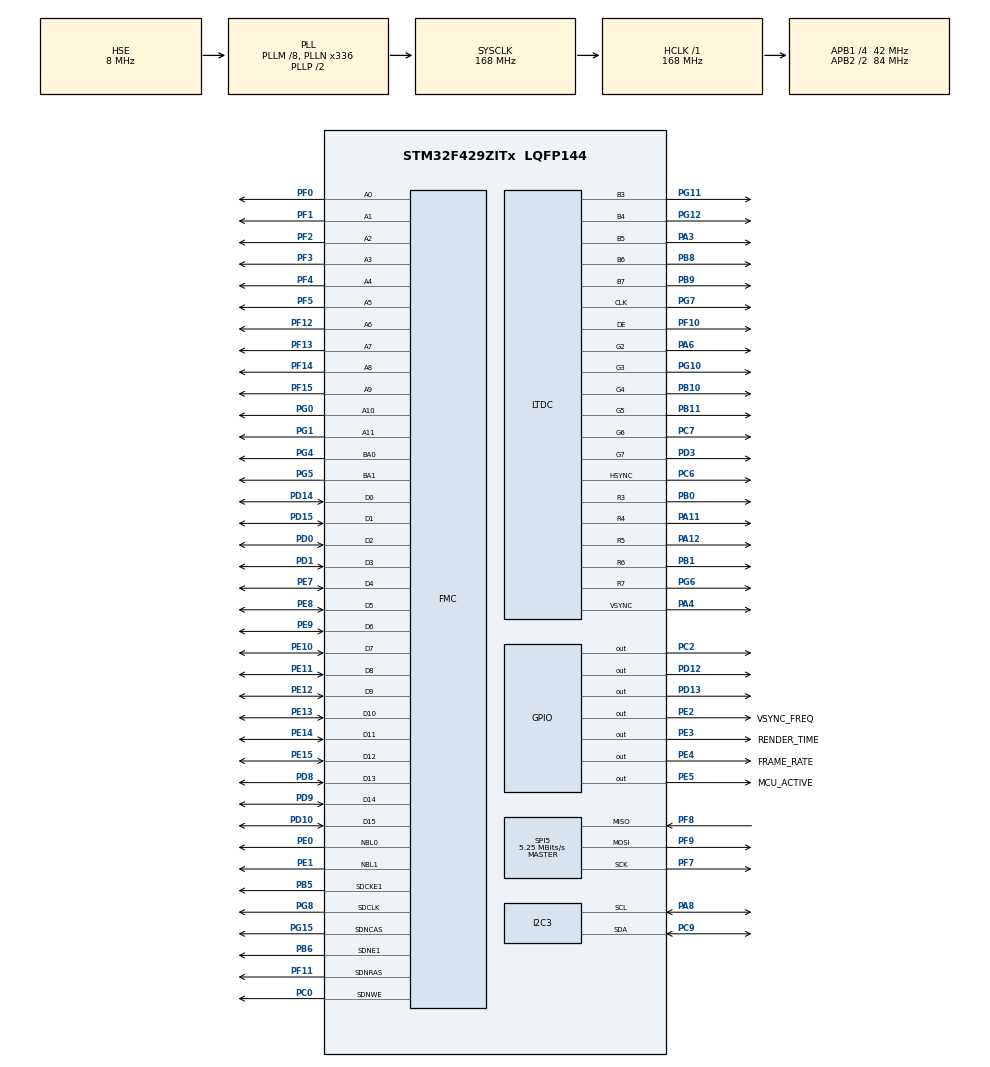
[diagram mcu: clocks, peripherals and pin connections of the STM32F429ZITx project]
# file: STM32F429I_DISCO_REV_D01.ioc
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DMA2D.ColorMode=DMA2D_OUTPUT_RGB565
FMC.CASLatency1=FMC_SDRAM_CAS_LATENCY_3
FMC.ExitSelfRefreshDelay1=7
FMC.LoadToActiveDelay1=2
FMC.RCDDelay1=2
FMC.RPDelay1=2
FMC.ReadPipeDelay1=FMC_SDRAM_RPIPE_DELAY_1
FMC.RowCycleDelay1=7
FMC.SDClockPeriod1=FMC_SDRAM_CLOCK_PERIOD_2
FMC.SelfRefreshTime1=4
FMC.WriteRecoveryTime1=3
FREERTOS.Tasks01=defaultTask,24,128,StartDefaultTask,Default,NULL,Dynamic,NULL,NULL;GUI_Task,24,8192,TouchGFX_Task,As external,NULL,Dynamic,NULL,NULL
FREERTOS.configMAX_PRIORITIES=56
FREERTOS.configTOTAL_HEAP_SIZE=65536
FREERTOS.configUSE_APPLICATION_TASK_TAG=1
I2C3.Analog_Filter=I2C_ANALOGFILTER_DISABLE
LTDC.ActiveH=320
LTDC.ActiveW=240
LTDC.Alpha_L0=255
LTDC.BlendingFactor1_L0=LTDC_BLENDING_FACTOR1_CA
LTDC.BlendingFactor2_L0=LTDC_BLENDING_FACTOR2_CA
LTDC.Blue_L0=0
LTDC.HBP=20
LTDC.HFP=10
LTDC.HSync=10
LTDC.ImageHeight_L0=320
LTDC.ImageWidth_L0=240
LTDC.Layers=0
LTDC.PixelFormat_L0=LTDC_PIXEL_FORMAT_RGB565
LTDC.VFP=4
LTDC.VSync=2
LTDC.WindowX1_L0=240
LTDC.WindowY1_L0=320
Mcu.Family=STM32F4
Mcu.Name=STM32F429ZITx
Mcu.Package=LQFP144
NVIC.DMA2D_IRQn=true\:5\:0\:true\:false\:true\:false\:true\:true\:true
NVIC.LTDC_IRQn=true\:5\:0\:true\:false\:true\:false\:true\:true\:true
NVIC.PriorityGroup=NVIC_PRIORITYGROUP_4
NVIC.TIM6_DAC_IRQn=true\:0\:0\:false\:false\:true\:false\:false\:true\:true
NVIC.TimeBase=TIM6_DAC_IRQn
NVIC.TimeBaseIP=TIM6
PA11.GPIO_Speed=GPIO_SPEED_FREQ_HIGH
PA11.Mode=RGB565
PA11.Signal=LTDC_R4
PA12.GPIO_Speed=GPIO_SPEED_FREQ_HIGH
PA12.Mode=RGB565
PA12.Signal=LTDC_R5
PA3.GPIO_Speed=GPIO_SPEED_FREQ_HIGH
PA3.Mode=RGB565
PA3.Signal=LTDC_B5
PA4.GPIO_Speed=GPIO_SPEED_FREQ_HIGH
PA4.Mode=RGB565
PA4.Signal=LTDC_VSYNC
PA6.GPIO_Speed=GPIO_SPEED_FREQ_HIGH
PA6.Mode=RGB565
PA6.Signal=LTDC_G2
PA8.GPIO_Pu=GPIO_PULLUP
PA8.Mode=I2C
PA8.Signal=I2C3_SCL
PB0.GPIO_Speed=GPIO_SPEED_FREQ_HIGH
PB0.Mode=RGB565
PB0.Signal=LTDC_R3
PB1.GPIO_Speed=GPIO_SPEED_FREQ_HIGH
PB1.Mode=RGB565
PB1.Signal=LTDC_R6
PB10.GPIO_Speed=GPIO_SPEED_FREQ_HIGH
PB10.Mode=RGB565
PB10.Signal=LTDC_G4
PB11.GPIO_Speed=GPIO_SPEED_FREQ_HIGH
PB11.Mode=RGB565
PB11.Signal=LTDC_G5
PB5.Mode=SdramChipSelect2_1
PB5.Signal=FMC_SDCKE1
PB6.Mode=SdramChipSelect2_1
PB6.Signal=FMC_SDNE1
PB8.GPIO_Speed=GPIO_SPEED_FREQ_HIGH
PB8.Mode=RGB565
PB8.Signal=LTDC_B6
PB9.GPIO_Speed=GPIO_SPEED_FREQ_HIGH
PB9.Mode=RGB565
PB9.Signal=LTDC_B7
PC0.Signal=FMC_SDNWE
PC2.GPIO_Speed=GPIO_SPEED_FREQ_HIGH
PC2.Signal=GPIO_Output
PC6.GPIO_Speed=GPIO_SPEED_FREQ_HIGH
PC6.Mode=RGB565
PC6.Signal=LTDC_HSYNC
PC7.GPIO_Speed=GPIO_SPEED_FREQ_HIGH
PC7.Mode=RGB565
PC7.Signal=LTDC_G6
PC9.GPIO_Pu=GPIO_PULLUP
PC9.Mode=I2C
PC9.Signal=I2C3_SDA
PD0.Signal=FMC_D2_DA2
PD1.Signal=FMC_D3_DA3
PD10.Signal=FMC_D15_DA15
PD12.GPIO_Speed=GPIO_SPEED_FREQ_HIGH
PD12.Signal=GPIO_Output
PD13.GPIO_Speed=GPIO_SPEED_FREQ_HIGH
PD13.Signal=GPIO_Output
PD14.Signal=FMC_D0_DA0
PD15.Signal=FMC_D1_DA1
PD3.GPIO_Speed=GPIO_SPEED_FREQ_HIGH
PD3.Mode=RGB565
PD3.Signal=LTDC_G7
PD8.Signal=FMC_D13_DA13
PD9.Signal=FMC_D14_DA14
PE0.Signal=FMC_NBL0
PE1.Signal=FMC_NBL1
PE10.Signal=FMC_D7_DA7
PE11.Signal=FMC_D8_DA8
PE12.Signal=FMC_D9_DA9
PE13.Signal=FMC_D10_DA10
PE14.Signal=FMC_D11_DA11
PE15.Signal=FMC_D12_DA12
PE2.GPIO_Label=VSYNC_FREQ
PE2.GPIO_Speed=GPIO_SPEED_FREQ_VERY_HIGH
PE2.Signal=GPIO_Output
PE3.GPIO_Label=RENDER_TIME
PE3.GPIO_Speed=GPIO_SPEED_FREQ_VERY_HIGH
PE3.Signal=GPIO_Output
PE4.GPIO_Label=FRAME_RATE
PE4.GPIO_Speed=GPIO_SPEED_FREQ_VERY_HIGH
PE4.Signal=GPIO_Output
PE5.GPIO_Label=MCU_ACTIVE
PE5.GPIO_Speed=GPIO_SPEED_FREQ_VERY_HIGH
PE5.Signal=GPIO_Output
PE7.Signal=FMC_D4_DA4
PE8.Signal=FMC_D5_DA5
PE9.Signal=FMC_D6_DA6
PF0.Signal=FMC_A0
PF1.Signal=FMC_A1
PF10.GPIO_Speed=GPIO_SPEED_FREQ_HIGH
PF10.Mode=RGB565
PF10.Signal=LTDC_DE
PF11.Signal=FMC_SDNRAS
PF12.Signal=FMC_A6
PF13.Signal=FMC_A7
PF14.Signal=FMC_A8
PF15.Signal=FMC_A9
PF2.Signal=FMC_A2
PF3.Signal=FMC_A3
PF4.Signal=FMC_A4
PF5.Signal=FMC_A5
PF7.Mode=Full_Duplex_Master
PF7.Signal=SPI5_SCK
PF8.Mode=Full_Duplex_Master
PF8.Signal=SPI5_MISO
PF9.Mode=Full_Duplex_Master
PF9.Signal=SPI5_MOSI
PG0.Signal=FMC_A10
PG1.Signal=FMC_A11
PG10.GPIO_Speed=GPIO_SPEED_FREQ_HIGH
PG10.Mode=RGB565
PG10.Signal=LTDC_G3
PG11.GPIO_Speed=GPIO_SPEED_FREQ_HIGH
PG11.Mode=RGB565
PG11.Signal=LTDC_B3
PG12.GPIO_Speed=GPIO_SPEED_FREQ_HIGH
PG12.Mode=RGB565
PG12.Signal=LTDC_B4
PG15.Signal=FMC_SDNCAS
PG4.Signal=FMC_A14_BA0
PG5.Signal=FMC_A15_BA1
PG6.GPIO_Speed=GPIO_SPEED_FREQ_HIGH
PG6.Mode=RGB565
PG6.Signal=LTDC_R7
PG7.GPIO_Speed=GPIO_SPEED_FREQ_HIGH
PG7.Mode=RGB565
PG7.Signal=LTDC_CLK
PG8.Signal=FMC_SDCLK
PH0/OSC_IN.Mode=HSE-External-Oscillator
PH0/OSC_IN.Signal=RCC_OSC_IN
PH1/OSC_OUT.Mode=HSE-External-Oscillator
PH1/OSC_OUT.Signal=RCC_OSC_OUT
ProjectManager.HeapSize=0xA00
ProjectManager.StackSize=0xA00
ProjectManager.TargetToolchain=STM32CubeIDE
RCC.48MHZClocksFreq_Value=84000000
RCC.AHBFreq_Value=168000000
RCC.APB1CLKDivider=RCC_HCLK_DIV4
RCC.APB1Freq_Value=42000000
RCC.APB1TimFreq_Value=84000000
RCC.APB2CLKDivider=RCC_HCLK_DIV2
RCC.APB2Freq_Value=84000000
RCC.APB2TimFreq_Value=168000000
RCC.CortexFreq_Value=168000000
RCC.HCLKFreq_Value=168000000
RCC.HSE_VALUE=8000000
RCC.HSI_VALUE=16000000
RCC.LSE_VALUE=32768
RCC.PLLM=8
RCC.PLLN=336
RCC.PLLSAIDivR=RCC_PLLSAIDIVR_8
RCC.PLLSAIN=192
RCC.PLLSAIR=4
RCC.PLLSourceVirtual=RCC_PLLSOURCE_HSE
RCC.SYSCLKFreq_VALUE=168000000
RCC.SYSCLKSource=RCC_SYSCLKSOURCE_PLLCLK
RCC.VCOOutputFreq_Value=336000000
SH.FMC_A0.0=FMC_A0,12b-sda1
SH.FMC_A1.0=FMC_A1,12b-sda1
SH.FMC_A10.0=FMC_A10,12b-sda1
SH.FMC_A11.0=FMC_A11,12b-sda1
SH.FMC_A14_BA0.0=FMC_BA0,FourSdramBanks1
SH.FMC_A15_BA1.0=FMC_BA1,FourSdramBanks1
SH.FMC_A2.0=FMC_A2,12b-sda1
SH.FMC_A3.0=FMC_A3,12b-sda1
SH.FMC_A4.0=FMC_A4,12b-sda1
SH.FMC_A5.0=FMC_A5,12b-sda1
SH.FMC_A6.0=FMC_A6,12b-sda1
SH.FMC_A7.0=FMC_A7,12b-sda1
SH.FMC_A8.0=FMC_A8,12b-sda1
SH.FMC_A9.0=FMC_A9,12b-sda1
SH.FMC_D0_DA0.0=FMC_D0,sd-16b-d1
SH.FMC_D10_DA10.0=FMC_D10,sd-16b-d1
SH.FMC_D11_DA11.0=FMC_D11,sd-16b-d1
SH.FMC_D12_DA12.0=FMC_D12,sd-16b-d1
SH.FMC_D13_DA13.0=FMC_D13,sd-16b-d1
SH.FMC_D14_DA14.0=FMC_D14,sd-16b-d1
SH.FMC_D15_DA15.0=FMC_D15,sd-16b-d1
SH.FMC_D1_DA1.0=FMC_D1,sd-16b-d1
SH.FMC_D2_DA2.0=FMC_D2,sd-16b-d1
SH.FMC_D3_DA3.0=FMC_D3,sd-16b-d1
SH.FMC_D4_DA4.0=FMC_D4,sd-16b-d1
SH.FMC_D5_DA5.0=FMC_D5,sd-16b-d1
SH.FMC_D6_DA6.0=FMC_D6,sd-16b-d1
SH.FMC_D7_DA7.0=FMC_D7,sd-16b-d1
SH.FMC_D8_DA8.0=FMC_D8,sd-16b-d1
SH.FMC_D9_DA9.0=FMC_D9,sd-16b-d1
SH.FMC_NBL0.0=FMC_NBL0,Sd2ByteEnable1
SH.FMC_NBL1.0=FMC_NBL1,Sd2ByteEnable1
SH.FMC_SDCLK.0=FMC_SDCLK,12b-sda1
SH.FMC_SDNCAS.0=FMC_SDNCAS,12b-sda1
SH.FMC_SDNRAS.0=FMC_SDNRAS,12b-sda1
SH.FMC_SDNWE.0=FMC_SDNWE,12b-sda1
SPI5.BaudRatePrescaler=SPI_BAUDRATEPRESCALER_16
SPI5.CLKPolarity=SPI_POLARITY_LOW
SPI5.CRCCalculation=SPI_CRCCALCULATION_DISABLE
SPI5.CalculateBaudRate=5.25 MBits/s
SPI5.Direction=SPI_DIRECTION_2LINES
SPI5.Mode=SPI_MODE_MASTER
SPI5.VirtualType=VM_MASTER
STMicroelectronics.X-CUBE-TOUCHGFX.4.22.0.ApplicationCcGraphicsJjApplication=TouchGFXOoGenerator
STMicroelectronics.X-CUBE-TOUCHGFX.4.22.0.tgfx_buffering_strategy=Double
STMicroelectronics.X-CUBE-TOUCHGFX.4.22.0.tgfx_display_interface=disp_ltdc
STMicroelectronics.X-CUBE-TOUCHGFX.4.22.0.tgfx_hardware_accelerator=dma_2d
STMicroelectronics.X-CUBE-TOUCHGFX.4.22.0.tgfx_vsync=vsync_ltdc
VP_CRC_VS_CRC.Mode=CRC_Activate
VP_DMA2D_VS_DMA2D.Mode=DMA2D_Activate
VP_FREERTOS_VS_CMSIS_V2.Mode=CMSIS_V2
VP_STMicroelectronics.X-CUBE-TOUCHGFX_VS_GraphicsJjApplication_4.22.0.Mode=GraphicsJjApplication
VP_SYS_VS_tim6.Mode=TIM6
board=custom

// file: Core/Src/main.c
/* USER CODE BEGIN Header */
/**
  ******************************************************************************
  * @file           : main.c
  * @brief          : Main program body
  ******************************************************************************
  * @attention
  *
  * <h2><center>&copy; Copyright (c) 2020 STMicroelectronics.
  * All rights reserved.</center></h2>
  *
  * This software component is licensed by ST under Ultimate Liberty license
  * SLA0044, the "License"; You may not use this file except in compliance with
  * the License. You may obtain a copy of the License at:
  *                             www.st.com/SLA0044
  *
  ******************************************************************************
  */
/* USER CODE END Header */
#include "main.h"
#include "cmsis_os.h"
#include "app_touchgfx.h"

/* USER CODE BEGIN Includes */
#include "Components/ili9341/ili9341.h"
/* USER CODE END Includes */

/* USER CODE BEGIN PD */
#define REFRESH_COUNT           ((uint32_t)1386)   /* SDRAM refresh counter */
#define SDRAM_TIMEOUT           ((uint32_t)0xFFFF)

/**
  * @brief  FMC SDRAM Mode definition register defines
  */
#define SDRAM_MODEREG_BURST_LENGTH_1             ((uint16_t)0x0000)
#define SDRAM_MODEREG_BURST_LENGTH_2             ((uint16_t)0x0001)
#define SDRAM_MODEREG_BURST_LENGTH_4             ((uint16_t)0x0002)
#define SDRAM_MODEREG_BURST_LENGTH_8             ((uint16_t)0x0004)
#define SDRAM_MODEREG_BURST_TYPE_SEQUENTIAL      ((uint16_t)0x0000)
#define SDRAM_MODEREG_BURST_TYPE_INTERLEAVED     ((uint16_t)0x0008)
#define SDRAM_MODEREG_CAS_LATENCY_2              ((uint16_t)0x0020)
#define SDRAM_MODEREG_CAS_LATENCY_3              ((uint16_t)0x0030)
#define SDRAM_MODEREG_OPERATING_MODE_STANDARD    ((uint16_t)0x0000)
#define SDRAM_MODEREG_WRITEBURST_MODE_PROGRAMMED ((uint16_t)0x0000)
#define SDRAM_MODEREG_WRITEBURST_MODE_SINGLE     ((uint16_t)0x0200)

#define I2C3_TIMEOUT_MAX                    0x3000 /*<! The value of the maximal timeout for I2C waiting loops */
#define SPI5_TIMEOUT_MAX                    0x1000
/* USER CODE END PD */

 CRC_HandleTypeDef hcrc;

DMA2D_HandleTypeDef hdma2d;

I2C_HandleTypeDef hi2c3;

LTDC_HandleTypeDef hltdc;

SPI_HandleTypeDef hspi5;

SDRAM_HandleTypeDef hsdram1;

/* Definitions for defaultTask */
osThreadId_t defaultTaskHandle;
const osThreadAttr_t defaultTask_attributes = {
  .name = "defaultTask",
  .stack_size = 128 * 4,
  .priority = (osPriority_t) osPriorityNormal,
};
/* Definitions for GUI_Task */
osThreadId_t GUI_TaskHandle;
const osThreadAttr_t GUI_Task_attributes = {
  .name = "GUI_Task",
  .stack_size = 8192 * 4,
  .priority = (osPriority_t) osPriorityNormal,
};
/* USER CODE BEGIN PV */
osMessageQueueId_t queue1;
osMessageQueueId_t Queue1Handle;
const osMessageQueueAttr_t Queue1_attributes = {
  .name = "Queue1"
};
//osMessageQueueId_t queue2;
//osMessageQueueId_t Queue2Handle;
//const osMessageQueueAttr_t Queue2_attributes = {
//  .name = "Queue2"
//};
osStatus_t r_state;
/* USER CODE END PV */

void SystemClock_Config(void);
static void MX_GPIO_Init(void);
static void MX_CRC_Init(void);
static void MX_I2C3_Init(void);
static void MX_SPI5_Init(void);
static void MX_FMC_Init(void);
static void MX_LTDC_Init(void);
static void MX_DMA2D_Init(void);
void StartDefaultTask(void *argument);
extern void TouchGFX_Task(void *argument);

/* USER CODE BEGIN PFP */
static void BSP_SDRAM_Initialization_Sequence(SDRAM_HandleTypeDef *hsdram, FMC_SDRAM_CommandTypeDef *Command);

static uint8_t            I2C3_ReadData(uint8_t Addr, uint8_t Reg);
static void               I2C3_WriteData(uint8_t Addr, uint8_t Reg, uint8_t Value);
static uint8_t            I2C3_ReadBuffer(uint8_t Addr, uint8_t Reg, uint8_t *pBuffer, uint16_t Length);

/* SPIx bus function */
static void               SPI5_Write(uint16_t Value);
static uint32_t           SPI5_Read(uint8_t ReadSize);
static void               SPI5_Error(void);

/* Link function for LCD peripheral */
void                      LCD_IO_Init(void);
void                      LCD_IO_WriteData(uint16_t RegValue);
void                      LCD_IO_WriteReg(uint8_t Reg);
uint32_t                  LCD_IO_ReadData(uint16_t RegValue, uint8_t ReadSize);
void                      LCD_Delay(uint32_t delay);

/* IOExpander IO functions */
void                      IOE_Init(void);
void                      IOE_ITConfig(void);
void                      IOE_Delay(uint32_t Delay);
void                      IOE_Write(uint8_t Addr, uint8_t Reg, uint8_t Value);
uint8_t                   IOE_Read(uint8_t Addr, uint8_t Reg);
uint16_t                  IOE_ReadMultiple(uint8_t Addr, uint8_t Reg, uint8_t *pBuffer, uint16_t Length);

/* USER CODE END PFP */

/* USER CODE BEGIN 0 */
static LCD_DrvTypeDef* LcdDrv;

uint32_t I2c3Timeout = I2C3_TIMEOUT_MAX; /*<! Value of Timeout when I2C communication fails */
uint32_t Spi5Timeout = SPI5_TIMEOUT_MAX; /*<! Value of Timeout when SPI communication fails */
/* USER CODE END 0 */

int main(void)
{

  /* MCU Configuration--------------------------------------------------------*/

  /* Reset of all peripherals, Initializes the Flash interface and the Systick. */
  HAL_Init();

  /* Configure the system clock */
  SystemClock_Config();

  /* Initialize all configured peripherals */
  MX_GPIO_Init();
  MX_CRC_Init();
  MX_I2C3_Init();
  MX_SPI5_Init();
  MX_FMC_Init();
  MX_LTDC_Init();
  MX_DMA2D_Init();
  MX_TouchGFX_Init();

  /* Init scheduler */
  osKernelInitialize();

  /* USER CODE BEGIN RTOS_QUEUES */
  /* creation of Queue1 */
  Queue1Handle = osMessageQueueNew (8, sizeof(uint8_t), &Queue1_attributes);
//  Queue2Handle = osMessageQueueNew (8, sizeof(uint8_t), &Queue2_attributes);
  /* USER CODE END RTOS_QUEUES */

  /* Create the thread(s) */
  /* creation of defaultTask */
  defaultTaskHandle = osThreadNew(StartDefaultTask, NULL, &defaultTask_attributes);

  /* creation of GUI_Task */
  GUI_TaskHandle = osThreadNew(TouchGFX_Task, NULL, &GUI_Task_attributes);

  /* Start scheduler */
  osKernelStart();

  /* We should never get here as control is now taken by the scheduler */
  /* Infinite loop */
  while (1)
  {

  }
}

void SystemClock_Config(void)
{
  RCC_OscInitTypeDef RCC_OscInitStruct = {0};
  RCC_ClkInitTypeDef RCC_ClkInitStruct = {0};

  /** Configure the main internal regulator output voltage
  */
  __HAL_RCC_PWR_CLK_ENABLE();
  __HAL_PWR_VOLTAGESCALING_CONFIG(PWR_REGULATOR_VOLTAGE_SCALE1);

  /** Initializes the RCC Oscillators according to the specified parameters
  * in the RCC_OscInitTypeDef structure.
  */
  RCC_OscInitStruct.OscillatorType = RCC_OSCILLATORTYPE_HSE;
  RCC_OscInitStruct.HSEState = RCC_HSE_ON;
  RCC_OscInitStruct.PLL.PLLState = RCC_PLL_ON;
  RCC_OscInitStruct.PLL.PLLSource = RCC_PLLSOURCE_HSE;
  RCC_OscInitStruct.PLL.PLLM = 8;
  RCC_OscInitStruct.PLL.PLLN = 336;
  RCC_OscInitStruct.PLL.PLLP = RCC_PLLP_DIV2;
  RCC_OscInitStruct.PLL.PLLQ = 4;
  if (HAL_RCC_OscConfig(&RCC_OscInitStruct) != HAL_OK)
  {
    Error_Handler();
  }

  /** Initializes the CPU, AHB and APB buses clocks
  */
  RCC_ClkInitStruct.ClockType = RCC_CLOCKTYPE_HCLK|RCC_CLOCKTYPE_SYSCLK
                              |RCC_CLOCKTYPE_PCLK1|RCC_CLOCKTYPE_PCLK2;
  RCC_ClkInitStruct.SYSCLKSource = RCC_SYSCLKSOURCE_PLLCLK;
  RCC_ClkInitStruct.AHBCLKDivider = RCC_SYSCLK_DIV1;
  RCC_ClkInitStruct.APB1CLKDivider = RCC_HCLK_DIV4;
  RCC_ClkInitStruct.APB2CLKDivider = RCC_HCLK_DIV2;

  if (HAL_RCC_ClockConfig(&RCC_ClkInitStruct, FLASH_LATENCY_5) != HAL_OK)
  {
    Error_Handler();
  }
}

static void MX_CRC_Init(void)
{

  hcrc.Instance = CRC;
  if (HAL_CRC_Init(&hcrc) != HAL_OK)
  {
    Error_Handler();
  }

}

static void MX_DMA2D_Init(void)
{

  hdma2d.Instance = DMA2D;
  hdma2d.Init.Mode = DMA2D_M2M;
  hdma2d.Init.ColorMode = DMA2D_OUTPUT_RGB565;
  hdma2d.Init.OutputOffset = 0;
  hdma2d.LayerCfg[1].InputOffset = 0;
  hdma2d.LayerCfg[1].InputColorMode = DMA2D_INPUT_RGB565;
  hdma2d.LayerCfg[1].AlphaMode = DMA2D_NO_MODIF_ALPHA;
  hdma2d.LayerCfg[1].InputAlpha = 0;
  if (HAL_DMA2D_Init(&hdma2d) != HAL_OK)
  {
    Error_Handler();
  }
  if (HAL_DMA2D_ConfigLayer(&hdma2d, 1) != HAL_OK)
  {
    Error_Handler();
  }

}

static void MX_I2C3_Init(void)
{

  hi2c3.Instance = I2C3;
  hi2c3.Init.ClockSpeed = 100000;
  hi2c3.Init.DutyCycle = I2C_DUTYCYCLE_2;
  hi2c3.Init.OwnAddress1 = 0;
  hi2c3.Init.AddressingMode = I2C_ADDRESSINGMODE_7BIT;
  hi2c3.Init.DualAddressMode = I2C_DUALADDRESS_DISABLE;
  hi2c3.Init.OwnAddress2 = 0;
  hi2c3.Init.GeneralCallMode = I2C_GENERALCALL_DISABLE;
  hi2c3.Init.NoStretchMode = I2C_NOSTRETCH_DISABLE;
  if (HAL_I2C_Init(&hi2c3) != HAL_OK)
  {
    Error_Handler();
  }

  /** Configure Analogue filter
  */
  if (HAL_I2CEx_ConfigAnalogFilter(&hi2c3, I2C_ANALOGFILTER_DISABLE) != HAL_OK)
  {
    Error_Handler();
  }

  /** Configure Digital filter
  */
  if (HAL_I2CEx_ConfigDigitalFilter(&hi2c3, 0) != HAL_OK)
  {
    Error_Handler();
  }

}

static void MX_LTDC_Init(void)
{

  LTDC_LayerCfgTypeDef pLayerCfg = {0};

  hltdc.Instance = LTDC;
  hltdc.Init.HSPolarity = LTDC_HSPOLARITY_AL;
  hltdc.Init.VSPolarity = LTDC_VSPOLARITY_AL;
  hltdc.Init.DEPolarity = LTDC_DEPOLARITY_AL;
  hltdc.Init.PCPolarity = LTDC_PCPOLARITY_IPC;
  hltdc.Init.HorizontalSync = 9;
  hltdc.Init.VerticalSync = 1;
  hltdc.Init.AccumulatedHBP = 29;
  hltdc.Init.AccumulatedVBP = 3;
  hltdc.Init.AccumulatedActiveW = 269;
  hltdc.Init.AccumulatedActiveH = 323;
  hltdc.Init.TotalWidth = 279;
  hltdc.Init.TotalHeigh = 327;
  hltdc.Init.Backcolor.Blue = 0;
  hltdc.Init.Backcolor.Green = 0;
  hltdc.Init.Backcolor.Red = 0;
  if (HAL_LTDC_Init(&hltdc) != HAL_OK)
  {
    Error_Handler();
  }
  pLayerCfg.WindowX0 = 0;
  pLayerCfg.WindowX1 = 240;
  pLayerCfg.WindowY0 = 0;
  pLayerCfg.WindowY1 = 320;
  pLayerCfg.PixelFormat = LTDC_PIXEL_FORMAT_RGB565;
  pLayerCfg.Alpha = 255;
  pLayerCfg.Alpha0 = 0;
  pLayerCfg.BlendingFactor1 = LTDC_BLENDING_FACTOR1_CA;
  pLayerCfg.BlendingFactor2 = LTDC_BLENDING_FACTOR2_CA;
  pLayerCfg.FBStartAdress = 0;
  pLayerCfg.ImageWidth = 240;
  pLayerCfg.ImageHeight = 320;
  pLayerCfg.Backcolor.Blue = 0;
  pLayerCfg.Backcolor.Green = 0;
  pLayerCfg.Backcolor.Red = 0;
  if (HAL_LTDC_ConfigLayer(&hltdc, &pLayerCfg, 0) != HAL_OK)
  {
    Error_Handler();
  }
  /* USER CODE BEGIN LTDC_Init 2 */
    /*Select the device */
  LcdDrv = &ili9341_drv;
  /* LCD Init */
  LcdDrv->Init();

  LcdDrv->DisplayOff();
  /* USER CODE END LTDC_Init 2 */

}

static void MX_SPI5_Init(void)
{

  /* SPI5 parameter configuration*/
  hspi5.Instance = SPI5;
  hspi5.Init.Mode = SPI_MODE_MASTER;
  hspi5.Init.Direction = SPI_DIRECTION_2LINES;
  hspi5.Init.DataSize = SPI_DATASIZE_8BIT;
  hspi5.Init.CLKPolarity = SPI_POLARITY_LOW;
  hspi5.Init.CLKPhase = SPI_PHASE_1EDGE;
  hspi5.Init.NSS = SPI_NSS_SOFT;
  hspi5.Init.BaudRatePrescaler = SPI_BAUDRATEPRESCALER_16;
  hspi5.Init.FirstBit = SPI_FIRSTBIT_MSB;
  hspi5.Init.TIMode = SPI_TIMODE_DISABLE;
  hspi5.Init.CRCCalculation = SPI_CRCCALCULATION_DISABLE;
  hspi5.Init.CRCPolynomial = 10;
  if (HAL_SPI_Init(&hspi5) != HAL_OK)
  {
    Error_Handler();
  }

}

/* FMC initialization function */
static void MX_FMC_Init(void)
{

  FMC_SDRAM_TimingTypeDef SdramTiming = {0};

  /** Perform the SDRAM1 memory initialization sequence
  */
  hsdram1.Instance = FMC_SDRAM_DEVICE;
  /* hsdram1.Init */
  hsdram1.Init.SDBank = FMC_SDRAM_BANK2;
  hsdram1.Init.ColumnBitsNumber = FMC_SDRAM_COLUMN_BITS_NUM_8;
  hsdram1.Init.RowBitsNumber = FMC_SDRAM_ROW_BITS_NUM_12;
  hsdram1.Init.MemoryDataWidth = FMC_SDRAM_MEM_BUS_WIDTH_16;
  hsdram1.Init.InternalBankNumber = FMC_SDRAM_INTERN_BANKS_NUM_4;
  hsdram1.Init.CASLatency = FMC_SDRAM_CAS_LATENCY_3;
  hsdram1.Init.WriteProtection = FMC_SDRAM_WRITE_PROTECTION_DISABLE;
  hsdram1.Init.SDClockPeriod = FMC_SDRAM_CLOCK_PERIOD_2;
  hsdram1.Init.ReadBurst = FMC_SDRAM_RBURST_DISABLE;
  hsdram1.Init.ReadPipeDelay = FMC_SDRAM_RPIPE_DELAY_1;
  /* SdramTiming */
  SdramTiming.LoadToActiveDelay = 2;
  SdramTiming.ExitSelfRefreshDelay = 7;
  SdramTiming.SelfRefreshTime = 4;
  SdramTiming.RowCycleDelay = 7;
  SdramTiming.WriteRecoveryTime = 3;
  SdramTiming.RPDelay = 2;
  SdramTiming.RCDDelay = 2;

  if (HAL_SDRAM_Init(&hsdram1, &SdramTiming) != HAL_OK)
  {
    Error_Handler( );
  }

  /* USER CODE BEGIN FMC_Init 2 */

  FMC_SDRAM_CommandTypeDef command;

  /* Program the SDRAM external device */
  BSP_SDRAM_Initialization_Sequence(&hsdram1, &command);
  /* USER CODE END FMC_Init 2 */
}

static void MX_GPIO_Init(void)
{
  GPIO_InitTypeDef GPIO_InitStruct = {0};

  /* GPIO Ports Clock Enable */
  __HAL_RCC_GPIOE_CLK_ENABLE();
  __HAL_RCC_GPIOF_CLK_ENABLE();
  __HAL_RCC_GPIOH_CLK_ENABLE();
  __HAL_RCC_GPIOC_CLK_ENABLE();
  __HAL_RCC_GPIOA_CLK_ENABLE();
  __HAL_RCC_GPIOB_CLK_ENABLE();
  __HAL_RCC_GPIOG_CLK_ENABLE();
  __HAL_RCC_GPIOD_CLK_ENABLE();

  /*Configure GPIO pin Output Level */
  HAL_GPIO_WritePin(GPIOE, VSYNC_FREQ_Pin|RENDER_TIME_Pin|FRAME_RATE_Pin|MCU_ACTIVE_Pin, GPIO_PIN_RESET);

  /*Configure GPIO pin Output Level */
  HAL_GPIO_WritePin(GPIOC, GPIO_PIN_2, GPIO_PIN_RESET);

  /*Configure GPIO pin Output Level */
  HAL_GPIO_WritePin(GPIOD, GPIO_PIN_12|GPIO_PIN_13, GPIO_PIN_RESET);

  /*Configure GPIO pins : VSYNC_FREQ_Pin RENDER_TIME_Pin FRAME_RATE_Pin MCU_ACTIVE_Pin */
  GPIO_InitStruct.Pin = VSYNC_FREQ_Pin|RENDER_TIME_Pin|FRAME_RATE_Pin|MCU_ACTIVE_Pin;
  GPIO_InitStruct.Mode = GPIO_MODE_OUTPUT_PP;
  GPIO_InitStruct.Pull = GPIO_NOPULL;
  GPIO_InitStruct.Speed = GPIO_SPEED_FREQ_VERY_HIGH;
  HAL_GPIO_Init(GPIOE, &GPIO_InitStruct);

  /*Configure GPIO pin : PC2 */
  GPIO_InitStruct.Pin = GPIO_PIN_2;
  GPIO_InitStruct.Mode = GPIO_MODE_OUTPUT_PP;
  GPIO_InitStruct.Pull = GPIO_NOPULL;
  GPIO_InitStruct.Speed = GPIO_SPEED_FREQ_HIGH;
  HAL_GPIO_Init(GPIOC, &GPIO_InitStruct);

  /*Configure GPIO pins : PD12 PD13 */
  GPIO_InitStruct.Pin = GPIO_PIN_12|GPIO_PIN_13;
  GPIO_InitStruct.Mode = GPIO_MODE_OUTPUT_PP;
  GPIO_InitStruct.Pull = GPIO_NOPULL;
  GPIO_InitStruct.Speed = GPIO_SPEED_FREQ_HIGH;
  HAL_GPIO_Init(GPIOD, &GPIO_InitStruct);

  /*Configure GPIO pin : PA0 interrupt rising edge*/
  GPIO_InitStruct.Pin = GPIO_PIN_0;
  GPIO_InitStruct.Mode = GPIO_MODE_INPUT;
  GPIO_InitStruct.Pull = GPIO_NOPULL;
  HAL_GPIO_Init(GPIOA, &GPIO_InitStruct);

  /*Configure GPIO pin : PG2 and PG3 for input */
  GPIO_InitStruct.Pin = GPIO_PIN_2 | GPIO_PIN_3;
  GPIO_InitStruct.Mode = GPIO_MODE_INPUT;
  GPIO_InitStruct.Pull = GPIO_PULLUP;
  HAL_GPIO_Init(GPIOG, &GPIO_InitStruct);

  /* EXTI interrupt init*/
  //HAL_NVIC_SetPriority(EXTI0_IRQn, configMAX_SYSCALL_INTERRUPT_PRIORITY+5 , 0);
  //HAL_NVIC_EnableIRQ(EXTI0_IRQn);
}

/* USER CODE BEGIN 4 */
/**
  * @brief  Perform the SDRAM external memory initialization sequence
  * @param  hsdram: SDRAM handle
  * @param  Command: Pointer to SDRAM command structure
  * @retval None
  */
static void BSP_SDRAM_Initialization_Sequence(SDRAM_HandleTypeDef *hsdram, FMC_SDRAM_CommandTypeDef *Command)
{
 __IO uint32_t tmpmrd =0;

  /* Step 1:  Configure a clock configuration enable command */
  Command->CommandMode             = FMC_SDRAM_CMD_CLK_ENABLE;
  Command->CommandTarget           = FMC_SDRAM_CMD_TARGET_BANK2;
  Command->AutoRefreshNumber       = 1;
  Command->ModeRegisterDefinition  = 0;

  /* Send the command */
  HAL_SDRAM_SendCommand(hsdram, Command, SDRAM_TIMEOUT);

  /* Step 2: Insert 100 us minimum delay */
  /* Inserted delay is equal to 1 ms due to systick time base unit (ms) */
  HAL_Delay(1);

  /* Step 3: Configure a PALL (precharge all) command */
  Command->CommandMode             = FMC_SDRAM_CMD_PALL;
  Command->CommandTarget           = FMC_SDRAM_CMD_TARGET_BANK2;
  Command->AutoRefreshNumber       = 1;
  Command->ModeRegisterDefinition  = 0;

  /* Send the command */
  HAL_SDRAM_SendCommand(hsdram, Command, SDRAM_TIMEOUT);

  /* Step 4: Configure an Auto Refresh command */
  Command->CommandMode             = FMC_SDRAM_CMD_AUTOREFRESH_MODE;
  Command->CommandTarget           = FMC_SDRAM_CMD_TARGET_BANK2;
  Command->AutoRefreshNumber       = 4;
  Command->ModeRegisterDefinition  = 0;

  /* Send the command */
  HAL_SDRAM_SendCommand(hsdram, Command, SDRAM_TIMEOUT);

  /* Step 5: Program the external memory mode register */
  tmpmrd = (uint32_t)SDRAM_MODEREG_BURST_LENGTH_1          |
                     SDRAM_MODEREG_BURST_TYPE_SEQUENTIAL   |
                     SDRAM_MODEREG_CAS_LATENCY_3           |
                     SDRAM_MODEREG_OPERATING_MODE_STANDARD |
                     SDRAM_MODEREG_WRITEBURST_MODE_SINGLE;

  Command->CommandMode             = FMC_SDRAM_CMD_LOAD_MODE;
  Command->CommandTarget           = FMC_SDRAM_CMD_TARGET_BANK2;
  Command->AutoRefreshNumber       = 1;
  Command->ModeRegisterDefinition  = tmpmrd;

  /* Send the command */
  HAL_SDRAM_SendCommand(hsdram, Command, SDRAM_TIMEOUT);

  /* Step 6: Set the refresh rate counter */
  /* Set the device refresh rate */
  HAL_SDRAM_ProgramRefreshRate(hsdram, REFRESH_COUNT);
}

/**
  * @brief  IOE Low Level Initialization.
  */
void IOE_Init(void)
{
  //Dummy function called when initializing to stmpe811 to setup the i2c.
  //This is done with cubmx and is therfore not done here.
}

/**
  * @brief  IOE Low Level Interrupt configuration.
  */
void IOE_ITConfig(void)
{
  //Dummy function called when initializing to stmpe811 to setup interupt for the i2c.
  //The interupt is not used in our case, therefore nothing is done here.
}

/**
  * @brief  IOE Writes single data operation.
  * @param  Addr: I2C Address
  * @param  Reg: Reg Address
  * @param  Value: Data to be written
  */
void IOE_Write(uint8_t Addr, uint8_t Reg, uint8_t Value)
{
  I2C3_WriteData(Addr, Reg, Value);
}

/**
  * @brief  IOE Reads single data.
  * @param  Addr: I2C Address
  * @param  Reg: Reg Address
  * @retval The read data
  */
uint8_t IOE_Read(uint8_t Addr, uint8_t Reg)
{
  return I2C3_ReadData(Addr, Reg);
}

/**
  * @brief  IOE Reads multiple data.
  * @param  Addr: I2C Address
  * @param  Reg: Reg Address
  * @param  pBuffer: pointer to data buffer
  * @param  Length: length of the data
  * @retval 0 if no problems to read multiple data
  */
uint16_t IOE_ReadMultiple(uint8_t Addr, uint8_t Reg, uint8_t *pBuffer, uint16_t Length)
{
 return I2C3_ReadBuffer(Addr, Reg, pBuffer, Length);
}

/**
  * @brief  IOE Delay.
  * @param  Delay in ms
  */
void IOE_Delay(uint32_t Delay)
{
  HAL_Delay(Delay);
}

/**
  * @brief  Writes a value in a register of the device through BUS.
  * @param  Addr: Device address on BUS Bus.
  * @param  Reg: The target register address to write
  * @param  Value: The target register value to be written
  */
static void I2C3_WriteData(uint8_t Addr, uint8_t Reg, uint8_t Value)
{
  HAL_StatusTypeDef status = HAL_OK;

  status = HAL_I2C_Mem_Write(&hi2c3, Addr, (uint16_t)Reg, I2C_MEMADD_SIZE_8BIT, &Value, 1, I2c3Timeout);

  /* Check the communication status */
  if(status != HAL_OK)
  {
    /* Re-Initialize the BUS */
    //I2Cx_Error();
  }
}

/**
  * @brief  Reads a register of the device through BUS.
  * @param  Addr: Device address on BUS Bus.
  * @param  Reg: The target register address to write
  * @retval Data read at register address
  */
static uint8_t I2C3_ReadData(uint8_t Addr, uint8_t Reg)
{
  HAL_StatusTypeDef status = HAL_OK;
  uint8_t value = 0;

  status = HAL_I2C_Mem_Read(&hi2c3, Addr, Reg, I2C_MEMADD_SIZE_8BIT, &value, 1, I2c3Timeout);

  /* Check the communication status */
  if(status != HAL_OK)
  {
    /* Re-Initialize the BUS */
    //I2Cx_Error();

  }
  return value;
}

/**
  * @brief  Reads multiple data on the BUS.
  * @param  Addr: I2C Address
  * @param  Reg: Reg Address
  * @param  pBuffer: pointer to read data buffer
  * @param  Length: length of the data
  * @retval 0 if no problems to read multiple data
  */
static uint8_t I2C3_ReadBuffer(uint8_t Addr, uint8_t Reg, uint8_t *pBuffer, uint16_t Length)
{
  HAL_StatusTypeDef status = HAL_OK;

  status = HAL_I2C_Mem_Read(&hi2c3, Addr, (uint16_t)Reg, I2C_MEMADD_SIZE_8BIT, pBuffer, Length, I2c3Timeout);

  /* Check the communication status */
  if(status == HAL_OK)
  {
    return 0;
  }
  else
  {
    /* Re-Initialize the BUS */
    //I2Cx_Error();

    return 1;
  }
}

/**
  * @brief  Reads 4 bytes from device.
  * @param  ReadSize: Number of bytes to read (max 4 bytes)
  * @retval Value read on the SPI
  */
static uint32_t SPI5_Read(uint8_t ReadSize)
{
  HAL_StatusTypeDef status = HAL_OK;
  uint32_t readvalue;

  status = HAL_SPI_Receive(&hspi5, (uint8_t*) &readvalue, ReadSize, Spi5Timeout);

  /* Check the communication status */
  if(status != HAL_OK)
  {
    /* Re-Initialize the BUS */
    SPI5_Error();
  }

  return readvalue;
}

/**
  * @brief  Writes a byte to device.
  * @param  Value: value to be written
  */
static void SPI5_Write(uint16_t Value)
{
  HAL_StatusTypeDef status = HAL_OK;

  status = HAL_SPI_Transmit(&hspi5, (uint8_t*) &Value, 1, Spi5Timeout);

  /* Check the communication status */
  if(status != HAL_OK)
  {
    /* Re-Initialize the BUS */
    SPI5_Error();
  }
}

/**
  * @brief  SPI5 error treatment function.
  */
static void SPI5_Error(void)
{
  /* De-initialize the SPI communication BUS */
  //HAL_SPI_DeInit(&SpiHandle);

  /* Re- Initialize the SPI communication BUS */
  //SPIx_Init();
}

void LCD_IO_Init(void)
{
  /* Set or Reset the control line */
  HAL_GPIO_WritePin(GPIOC, GPIO_PIN_2, GPIO_PIN_RESET);
  HAL_GPIO_WritePin(GPIOC, GPIO_PIN_2, GPIO_PIN_SET);
}

/**
  * @brief  Writes register value.
  */
void LCD_IO_WriteData(uint16_t RegValue)
{
  /* Set WRX to send data */
  HAL_GPIO_WritePin(GPIOD, GPIO_PIN_13, GPIO_PIN_SET);

  /* Reset LCD control line(/CS) and Send data */
  HAL_GPIO_WritePin(GPIOC, GPIO_PIN_2, GPIO_PIN_RESET);
  SPI5_Write(RegValue);

  /* Deselect: Chip Select high */
  HAL_GPIO_WritePin(GPIOC, GPIO_PIN_2, GPIO_PIN_SET);
}

/**
  * @brief  Writes register address.
  */
void LCD_IO_WriteReg(uint8_t Reg)
{
  /* Reset WRX to send command */
  HAL_GPIO_WritePin(GPIOD, GPIO_PIN_13, GPIO_PIN_RESET);

  /* Reset LCD control line(/CS) and Send command */
  HAL_GPIO_WritePin(GPIOC, GPIO_PIN_2, GPIO_PIN_RESET);
  SPI5_Write(Reg);

  /* Deselect: Chip Select high */
  HAL_GPIO_WritePin(GPIOC, GPIO_PIN_2, GPIO_PIN_SET);
}

/**
  * @brief  Reads register value.
  * @param  RegValue Address of the register to read
  * @param  ReadSize Number of bytes to read
  * @retval Content of the register value
  */
uint32_t LCD_IO_ReadData(uint16_t RegValue, uint8_t ReadSize)
{
  uint32_t readvalue = 0;

  /* Select: Chip Select low */
  HAL_GPIO_WritePin(GPIOC, GPIO_PIN_2, GPIO_PIN_RESET);

  /* Reset WRX to send command */
  HAL_GPIO_WritePin(GPIOD, GPIO_PIN_13, GPIO_PIN_RESET);

  SPI5_Write(RegValue);

  readvalue = SPI5_Read(ReadSize);

  /* Set WRX to send data */
  HAL_GPIO_WritePin(GPIOD, GPIO_PIN_13, GPIO_PIN_SET);

  /* Deselect: Chip Select high */
  HAL_GPIO_WritePin(GPIOC, GPIO_PIN_2, GPIO_PIN_SET);

  return readvalue;
}

/**
  * @brief  Wait for loop in ms.
  * @param  Delay in ms.
  */
void LCD_Delay(uint32_t Delay)
{
  HAL_Delay(Delay);
}

/* USER CODE END 4 */

void StartDefaultTask(void *argument)
{
  /* USER CODE BEGIN 5 */
  /* Infinite loop */
  for(;;)
  {
	  if(HAL_GPIO_ReadPin(GPIOG, GPIO_PIN_2) == GPIO_PIN_RESET) {
	  		uint32_t count = osMessageQueueGetCount(Queue1Handle);
	  		if(count < 2) {
	  			uint8_t x = 'R';
	  			osMessageQueuePut(Queue1Handle, &x, 0, 200);
	  		}
	  	}
	  if(HAL_GPIO_ReadPin(GPIOG, GPIO_PIN_3) == GPIO_PIN_RESET) {
	  	  	uint32_t count = osMessageQueueGetCount(Queue1Handle);
	  	  	if(count < 2) {
	  	  		uint8_t y = 'L';
	  	  		osMessageQueuePut(Queue1Handle, &y, 0, 200);
	  	  		}
	  	  	}
	osDelay(10);
  }
  /* USER CODE END 5 */
}

void HAL_TIM_PeriodElapsedCallback(TIM_HandleTypeDef *htim)
{
  if (htim->Instance == TIM6) {
    HAL_IncTick();
  }
}

void Error_Handler(void)
{
}
